One B-rep face of a CAD part: STEP entity #78618.
In plain terms, the planar face has unit normal (0, 0, 1).
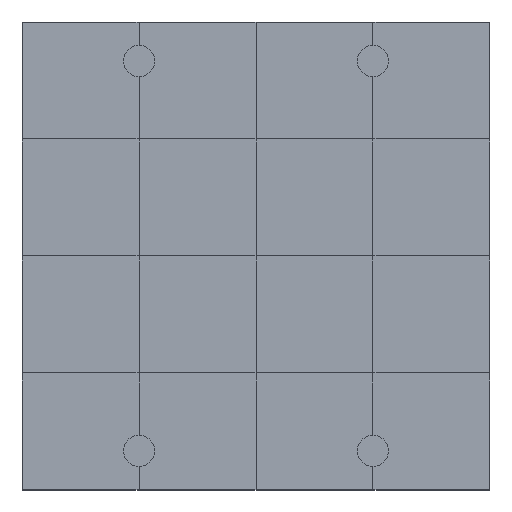
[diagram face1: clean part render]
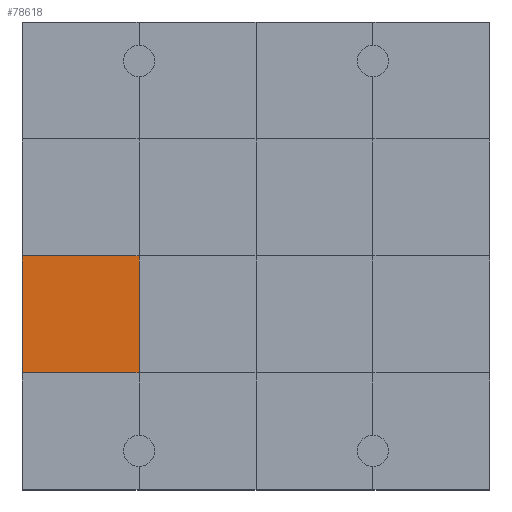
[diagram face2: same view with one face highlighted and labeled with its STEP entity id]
Its self-contained STEP definition (entity closure, numbers rounded to 3 decimals):
#78168 = VERTEX_POINT('',#78169);
#78169 = CARTESIAN_POINT('',(0.,3.,1.2));
#78183 = PLANE('',#78184);
#78184 = AXIS2_PLACEMENT_3D('',#78185,#78186,#78187);
#78185 = CARTESIAN_POINT('',(0.,3.,0.));
#78186 = DIRECTION('',(1.,0.,-0.));
#78187 = DIRECTION('',(0.,0.,1.));
#78209 = PLANE('',#78210);
#78210 = AXIS2_PLACEMENT_3D('',#78211,#78212,#78213);
#78211 = CARTESIAN_POINT('',(0.,0.,1.2));
#78212 = DIRECTION('',(0.,0.,1.));
#78213 = DIRECTION('',(1.,0.,-0.));
#78360 = VERTEX_POINT('',#78361);
#78361 = CARTESIAN_POINT('',(3.,3.,1.2));
#78382 = EDGE_CURVE('',#78168,#78360,#78383,.T.);
#78383 = SURFACE_CURVE('',#78384,(#78388,#78395),.PCURVE_S1.);
#78384 = LINE('',#78385,#78386);
#78385 = CARTESIAN_POINT('',(0.,3.,1.2));
#78386 = VECTOR('',#78387,1.);
#78387 = DIRECTION('',(1.,0.,-0.));
#78388 = PCURVE('',#78209,#78389);
#78389 = DEFINITIONAL_REPRESENTATION('',(#78390),#78394);
#78390 = LINE('',#78391,#78392);
#78391 = CARTESIAN_POINT('',(0.,3.));
#78392 = VECTOR('',#78393,1.);
#78393 = DIRECTION('',(1.,0.));
#78394 = ( GEOMETRIC_REPRESENTATION_CONTEXT(2) 
PARAMETRIC_REPRESENTATION_CONTEXT() REPRESENTATION_CONTEXT('2D SPACE',''
  ) );
#78395 = PCURVE('',#78396,#78401);
#78396 = PLANE('',#78397);
#78397 = AXIS2_PLACEMENT_3D('',#78398,#78399,#78400);
#78398 = CARTESIAN_POINT('',(0.,3.,1.2));
#78399 = DIRECTION('',(0.,0.,1.));
#78400 = DIRECTION('',(1.,0.,-0.));
#78401 = DEFINITIONAL_REPRESENTATION('',(#78402),#78406);
#78402 = LINE('',#78403,#78404);
#78403 = CARTESIAN_POINT('',(0.,0.));
#78404 = VECTOR('',#78405,1.);
#78405 = DIRECTION('',(1.,0.));
#78406 = ( GEOMETRIC_REPRESENTATION_CONTEXT(2) 
PARAMETRIC_REPRESENTATION_CONTEXT() REPRESENTATION_CONTEXT('2D SPACE',''
  ) );
#78441 = VERTEX_POINT('',#78442);
#78442 = CARTESIAN_POINT('',(0.,6.,1.2));
#78468 = EDGE_CURVE('',#78168,#78441,#78469,.T.);
#78469 = SURFACE_CURVE('',#78470,(#78474,#78481),.PCURVE_S1.);
#78470 = LINE('',#78471,#78472);
#78471 = CARTESIAN_POINT('',(0.,3.,1.2));
#78472 = VECTOR('',#78473,1.);
#78473 = DIRECTION('',(-0.,1.,0.));
#78474 = PCURVE('',#78183,#78475);
#78475 = DEFINITIONAL_REPRESENTATION('',(#78476),#78480);
#78476 = LINE('',#78477,#78478);
#78477 = CARTESIAN_POINT('',(1.2,0.));
#78478 = VECTOR('',#78479,1.);
#78479 = DIRECTION('',(0.,-1.));
#78480 = ( GEOMETRIC_REPRESENTATION_CONTEXT(2) 
PARAMETRIC_REPRESENTATION_CONTEXT() REPRESENTATION_CONTEXT('2D SPACE',''
  ) );
#78481 = PCURVE('',#78396,#78482);
#78482 = DEFINITIONAL_REPRESENTATION('',(#78483),#78487);
#78483 = LINE('',#78484,#78485);
#78484 = CARTESIAN_POINT('',(0.,0.));
#78485 = VECTOR('',#78486,1.);
#78486 = DIRECTION('',(0.,1.));
#78487 = ( GEOMETRIC_REPRESENTATION_CONTEXT(2) 
PARAMETRIC_REPRESENTATION_CONTEXT() REPRESENTATION_CONTEXT('2D SPACE',''
  ) );
#78618 = ADVANCED_FACE('',(#78619),#78396,.T.);
#78619 = FACE_BOUND('',#78620,.T.);
#78620 = EDGE_LOOP('',(#78621,#78622,#78623,#78651));
#78621 = ORIENTED_EDGE('',*,*,#78468,.F.);
#78622 = ORIENTED_EDGE('',*,*,#78382,.T.);
#78623 = ORIENTED_EDGE('',*,*,#78624,.T.);
#78624 = EDGE_CURVE('',#78360,#78625,#78627,.T.);
#78625 = VERTEX_POINT('',#78626);
#78626 = CARTESIAN_POINT('',(3.,6.,1.2));
#78627 = SURFACE_CURVE('',#78628,(#78632,#78639),.PCURVE_S1.);
#78628 = LINE('',#78629,#78630);
#78629 = CARTESIAN_POINT('',(3.,3.,1.2));
#78630 = VECTOR('',#78631,1.);
#78631 = DIRECTION('',(-0.,1.,0.));
#78632 = PCURVE('',#78396,#78633);
#78633 = DEFINITIONAL_REPRESENTATION('',(#78634),#78638);
#78634 = LINE('',#78635,#78636);
#78635 = CARTESIAN_POINT('',(3.,0.));
#78636 = VECTOR('',#78637,1.);
#78637 = DIRECTION('',(0.,1.));
#78638 = ( GEOMETRIC_REPRESENTATION_CONTEXT(2) 
PARAMETRIC_REPRESENTATION_CONTEXT() REPRESENTATION_CONTEXT('2D SPACE',''
  ) );
#78639 = PCURVE('',#78640,#78645);
#78640 = PLANE('',#78641);
#78641 = AXIS2_PLACEMENT_3D('',#78642,#78643,#78644);
#78642 = CARTESIAN_POINT('',(3.,3.,1.2));
#78643 = DIRECTION('',(0.,0.,1.));
#78644 = DIRECTION('',(1.,0.,-0.));
#78645 = DEFINITIONAL_REPRESENTATION('',(#78646),#78650);
#78646 = LINE('',#78647,#78648);
#78647 = CARTESIAN_POINT('',(0.,0.));
#78648 = VECTOR('',#78649,1.);
#78649 = DIRECTION('',(0.,1.));
#78650 = ( GEOMETRIC_REPRESENTATION_CONTEXT(2) 
PARAMETRIC_REPRESENTATION_CONTEXT() REPRESENTATION_CONTEXT('2D SPACE',''
  ) );
#78651 = ORIENTED_EDGE('',*,*,#78652,.F.);
#78652 = EDGE_CURVE('',#78441,#78625,#78653,.T.);
#78653 = SURFACE_CURVE('',#78654,(#78658,#78665),.PCURVE_S1.);
#78654 = LINE('',#78655,#78656);
#78655 = CARTESIAN_POINT('',(0.,6.,1.2));
#78656 = VECTOR('',#78657,1.);
#78657 = DIRECTION('',(1.,0.,-0.));
#78658 = PCURVE('',#78396,#78659);
#78659 = DEFINITIONAL_REPRESENTATION('',(#78660),#78664);
#78660 = LINE('',#78661,#78662);
#78661 = CARTESIAN_POINT('',(0.,3.));
#78662 = VECTOR('',#78663,1.);
#78663 = DIRECTION('',(1.,0.));
#78664 = ( GEOMETRIC_REPRESENTATION_CONTEXT(2) 
PARAMETRIC_REPRESENTATION_CONTEXT() REPRESENTATION_CONTEXT('2D SPACE',''
  ) );
#78665 = PCURVE('',#78666,#78671);
#78666 = PLANE('',#78667);
#78667 = AXIS2_PLACEMENT_3D('',#78668,#78669,#78670);
#78668 = CARTESIAN_POINT('',(0.,6.,1.2));
#78669 = DIRECTION('',(0.,0.,1.));
#78670 = DIRECTION('',(1.,0.,-0.));
#78671 = DEFINITIONAL_REPRESENTATION('',(#78672),#78676);
#78672 = LINE('',#78673,#78674);
#78673 = CARTESIAN_POINT('',(0.,0.));
#78674 = VECTOR('',#78675,1.);
#78675 = DIRECTION('',(1.,0.));
#78676 = ( GEOMETRIC_REPRESENTATION_CONTEXT(2) 
PARAMETRIC_REPRESENTATION_CONTEXT() REPRESENTATION_CONTEXT('2D SPACE',''
  ) );
